VERSION 5.8 ;
BUSBITCHARS "[]" ;
DIVIDERCHAR "/" ;
UNITS
    DATABASE MICRONS 1000 ;
END UNITS

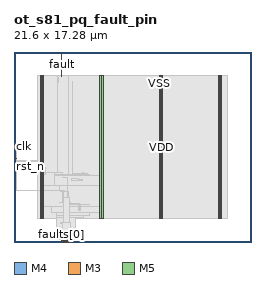
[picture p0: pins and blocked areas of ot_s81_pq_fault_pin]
MACRO ot_s81_pq_fault_pin
  FOREIGN ot_s81_pq_fault_pin 0 0 ;
  CLASS BLOCK ;
  SIZE 21.6 BY 17.28 ;
  PIN clk
    DIRECTION INPUT ;
    USE SIGNAL ;
    PORT
      LAYER M4 ;
        RECT  0 8.64 0.192 8.664 ;
    END
    PORT
      LAYER M4 ;
        RECT  0.156 8.64 0.275 8.664 ;
    END
  END clk
  PIN fault
    DIRECTION OUTPUT ;
    USE SIGNAL ;
    PORT
      LAYER M3 ;
        RECT  4.32 17.136 4.338 17.28 ;
    END
    PORT
      LAYER M3 ;
        RECT  4.32 15.061 4.338 17.148 ;
    END
  END fault
  PIN faults[0]
    DIRECTION INPUT ;
    USE SIGNAL ;
    PORT
      LAYER M3 ;
        RECT  4.32 0 4.338 0.144 ;
    END
  END faults[0]
  PIN faults[10]
    DIRECTION INPUT ;
    USE SIGNAL ;
    PORT
      LAYER M3 ;
        RECT  4.86 0 4.878 0.144 ;
    END
  END faults[10]
  PIN faults[11]
    DIRECTION INPUT ;
    USE SIGNAL ;
    PORT
      LAYER M5 ;
        RECT  4.8 0 4.824 0.192 ;
    END
  END faults[11]
  PIN faults[12]
    DIRECTION INPUT ;
    USE SIGNAL ;
    PORT
      LAYER M3 ;
        RECT  4.968 0 4.986 0.144 ;
    END
  END faults[12]
  PIN faults[13]
    DIRECTION INPUT ;
    USE SIGNAL ;
    PORT
      LAYER M5 ;
        RECT  4.896 0 4.92 0.192 ;
    END
  END faults[13]
  PIN faults[14]
    DIRECTION INPUT ;
    USE SIGNAL ;
    PORT
      LAYER M3 ;
        RECT  5.076 0 5.094 0.144 ;
    END
  END faults[14]
  PIN faults[15]
    DIRECTION INPUT ;
    USE SIGNAL ;
    PORT
      LAYER M5 ;
        RECT  4.992 0 5.016 0.192 ;
    END
  END faults[15]
  PIN faults[16]
    DIRECTION INPUT ;
    USE SIGNAL ;
    PORT
      LAYER M3 ;
        RECT  5.184 0 5.202 0.144 ;
    END
  END faults[16]
  PIN faults[17]
    DIRECTION INPUT ;
    USE SIGNAL ;
    PORT
      LAYER M5 ;
        RECT  5.088 0 5.112 0.192 ;
    END
  END faults[17]
  PIN faults[1]
    DIRECTION INPUT ;
    USE SIGNAL ;
    PORT
      LAYER M5 ;
        RECT  4.32 0 4.344 0.192 ;
    END
  END faults[1]
  PIN faults[2]
    DIRECTION INPUT ;
    USE SIGNAL ;
    PORT
      LAYER M3 ;
        RECT  4.428 0 4.446 0.144 ;
    END
  END faults[2]
  PIN faults[3]
    DIRECTION INPUT ;
    USE SIGNAL ;
    PORT
      LAYER M5 ;
        RECT  4.416 0 4.44 0.192 ;
    END
  END faults[3]
  PIN faults[4]
    DIRECTION INPUT ;
    USE SIGNAL ;
    PORT
      LAYER M3 ;
        RECT  4.536 0 4.554 0.144 ;
    END
  END faults[4]
  PIN faults[5]
    DIRECTION INPUT ;
    USE SIGNAL ;
    PORT
      LAYER M5 ;
        RECT  4.512 0 4.536 0.192 ;
    END
  END faults[5]
  PIN faults[6]
    DIRECTION INPUT ;
    USE SIGNAL ;
    PORT
      LAYER M3 ;
        RECT  4.644 0 4.662 0.144 ;
    END
  END faults[6]
  PIN faults[7]
    DIRECTION INPUT ;
    USE SIGNAL ;
    PORT
      LAYER M5 ;
        RECT  4.608 0 4.632 0.192 ;
    END
  END faults[7]
  PIN faults[8]
    DIRECTION INPUT ;
    USE SIGNAL ;
    PORT
      LAYER M3 ;
        RECT  4.752 0 4.77 0.144 ;
    END
  END faults[8]
  PIN faults[9]
    DIRECTION INPUT ;
    USE SIGNAL ;
    PORT
      LAYER M5 ;
        RECT  4.704 0 4.728 0.192 ;
    END
  END faults[9]
  PIN rst_n
    DIRECTION INPUT ;
    USE SIGNAL ;
    PORT
      LAYER M4 ;
        RECT  0 7.584 0.192 7.608 ;
    END
    PORT
      LAYER M4 ;
        RECT  0.156 7.584 0.245 7.608 ;
    END
  END rst_n
  PIN VDD
    DIRECTION INOUT ;
    USE POWER ;
    PORT
      LAYER M5 ;
        RECT  18.792 2.151 18.912 15.129 ;
        RECT  13.392 2.151 13.512 15.129 ;
        RECT  7.992 2.151 8.112 15.129 ;
        RECT  2.592 2.151 2.712 15.129 ;
    END
  END VDD
  PIN VSS
    DIRECTION INOUT ;
    USE GROUND ;
    PORT
      LAYER M5 ;
        RECT  18.6 2.137 18.72 15.143 ;
        RECT  13.2 2.137 13.32 15.143 ;
        RECT  7.8 2.137 7.92 15.143 ;
        RECT  2.4 2.137 2.52 15.143 ;
    END
  END VSS
  # OT_OBS_CLOSED layer=M5 d_um=1.536 added=0
  OBS
    LAYER RVTN ;
     RECT  2.16 2.16 19.44 2.295 ;
     RECT  2.16 2.565 19.44 2.835 ;
     RECT  2.16 3.105 19.44 3.375 ;
     RECT  2.16 3.645 19.44 3.915 ;
     RECT  2.16 4.185 19.44 4.455 ;
     RECT  2.16 4.725 19.44 4.995 ;
     RECT  2.16 5.265 19.44 5.535 ;
     RECT  2.16 5.805 19.44 6.075 ;
     RECT  2.16 6.345 19.44 6.615 ;
     RECT  2.16 6.885 19.44 7.155 ;
     RECT  2.16 7.425 19.44 7.695 ;
     RECT  2.16 7.965 19.44 8.235 ;
     RECT  2.16 8.505 19.44 8.775 ;
     RECT  2.16 9.045 19.44 9.315 ;
     RECT  2.16 9.585 19.44 9.855 ;
     RECT  2.16 10.125 19.44 10.395 ;
     RECT  2.16 10.665 19.44 10.935 ;
     RECT  2.16 11.205 19.44 11.475 ;
     RECT  2.16 11.745 19.44 12.015 ;
     RECT  2.16 12.285 19.44 12.555 ;
     RECT  2.16 12.825 19.44 13.095 ;
     RECT  2.16 13.365 19.44 13.635 ;
     RECT  2.16 13.905 19.44 14.175 ;
     RECT  2.16 14.445 19.44 14.715 ;
     RECT  2.16 14.985 19.44 15.12 ;
    LAYER RVTP ;
     RECT  2.16 2.295 19.44 2.565 ;
     RECT  2.16 2.835 19.44 3.105 ;
     RECT  2.16 3.375 19.44 3.645 ;
     RECT  2.16 3.915 19.44 4.185 ;
     RECT  2.16 4.455 19.44 4.725 ;
     RECT  2.16 4.995 19.44 5.265 ;
     RECT  2.16 5.535 19.44 5.805 ;
     RECT  2.16 6.075 19.44 6.345 ;
     RECT  2.16 6.615 19.44 6.885 ;
     RECT  2.16 7.155 19.44 7.425 ;
     RECT  2.16 7.695 19.44 7.965 ;
     RECT  2.16 8.235 19.44 8.505 ;
     RECT  2.16 8.775 19.44 9.045 ;
     RECT  2.16 9.315 19.44 9.585 ;
     RECT  2.16 9.855 19.44 10.125 ;
     RECT  2.16 10.395 19.44 10.665 ;
     RECT  2.16 10.935 19.44 11.205 ;
     RECT  2.16 11.475 19.44 11.745 ;
     RECT  2.16 12.015 19.44 12.285 ;
     RECT  2.16 12.555 19.44 12.825 ;
     RECT  2.16 13.095 19.44 13.365 ;
     RECT  2.16 13.635 19.44 13.905 ;
     RECT  2.16 14.175 19.44 14.445 ;
     RECT  2.16 14.715 19.44 14.985 ;
    LAYER M1 ;
     RECT  2.16 2.151 19.44 15.129 ;
    LAYER M2 ;
     RECT  0.211 7.362 2.16 7.38 ;
     RECT  2.16 2.151 3.955 15.129 ;
     RECT  3.955 2.106 4.919 15.129 ;
     RECT  4.855 0.144 4.963 0.162 ;
     RECT  4.963 0.144 5.135 0.234 ;
     RECT  5.135 0.216 5.567 0.234 ;
     RECT  4.919 2.151 19.44 15.129 ;
    LAYER M3 ;
     RECT  4.32 0.108 5.202 0.187 ;
     RECT  3.852 0.187 5.346 0.211 ;
     RECT  3.852 0.211 5.562 2.263 ;
     RECT  6.3 2.191 6.318 2.263 ;
     RECT  3.852 2.263 6.318 2.371 ;
     RECT  2.415 2.143 2.505 2.413 ;
     RECT  7.815 2.143 7.905 2.413 ;
     RECT  13.215 2.143 13.305 2.413 ;
     RECT  18.615 2.143 18.705 2.413 ;
     RECT  3.852 2.371 6.822 2.641 ;
     RECT  7.815 2.413 8.097 2.641 ;
     RECT  2.415 2.413 2.697 3.271 ;
     RECT  3.42 2.641 8.097 3.271 ;
     RECT  2.415 3.271 8.097 5.117 ;
     RECT  3.708 5.117 8.097 6.071 ;
     RECT  3.708 6.071 6.858 6.107 ;
     RECT  2.415 5.117 2.697 6.115 ;
     RECT  3.708 6.107 6.678 6.143 ;
     RECT  5.292 6.143 6.678 6.269 ;
     RECT  2.415 6.115 2.862 6.277 ;
     RECT  3.708 6.143 4.374 6.277 ;
     RECT  6.228 6.269 6.282 6.305 ;
     RECT  2.415 6.277 4.374 6.317 ;
     RECT  4.068 6.317 4.086 6.341 ;
     RECT  6.264 6.305 6.282 6.341 ;
     RECT  2.415 6.317 2.862 6.809 ;
     RECT  2.415 6.809 2.697 6.925 ;
     RECT  2.376 6.925 2.697 7.349 ;
     RECT  0.216 7.357 0.234 7.613 ;
     RECT  3.924 14.521 4.086 14.639 ;
     RECT  5.292 6.269 5.31 14.639 ;
     RECT  2.415 7.349 2.697 14.867 ;
     RECT  7.815 6.071 8.097 14.867 ;
     RECT  13.215 2.413 13.497 14.867 ;
     RECT  18.615 2.413 18.897 14.867 ;
     RECT  4.068 14.639 4.086 14.945 ;
     RECT  2.415 14.867 2.505 15.137 ;
     RECT  7.815 14.867 7.905 15.137 ;
     RECT  13.215 14.867 13.305 15.137 ;
     RECT  18.615 14.867 18.705 15.137 ;
    LAYER M4 ;
     RECT  0.229 4.704 2.408 4.728 ;
     RECT  2.408 2.148 2.512 15.132 ;
     RECT  2.512 2.418 2.704 14.862 ;
     RECT  2.704 4.704 4.097 5.112 ;
     RECT  4.097 4.704 4.273 4.728 ;
     RECT  4.129 3.552 4.381 3.576 ;
     RECT  4.273 4.56 4.381 4.728 ;
     RECT  2.704 6.288 4.385 6.312 ;
     RECT  4.381 3.552 4.525 4.728 ;
     RECT  3.841 0.192 4.556 0.216 ;
     RECT  4.525 3.456 4.565 4.728 ;
     RECT  4.273 1.728 4.652 1.752 ;
     RECT  4.565 3.456 4.669 4.632 ;
     RECT  4.652 1.728 4.739 2.28 ;
     RECT  4.669 3.36 4.796 4.632 ;
     RECT  4.796 2.784 4.883 4.632 ;
     RECT  4.453 5.856 4.883 5.88 ;
     RECT  4.556 0.192 4.885 0.552 ;
     RECT  4.883 3.456 4.924 4.632 ;
     RECT  4.885 0.192 4.969 0.6 ;
     RECT  4.924 3.456 5.027 4.008 ;
     RECT  4.739 1.728 5.123 1.752 ;
     RECT  5.027 3.456 5.177 3.624 ;
     RECT  4.969 0.192 5.357 0.216 ;
     RECT  5.177 3.456 5.893 3.48 ;
     RECT  5.209 5.616 5.897 5.784 ;
     RECT  5.893 2.88 5.933 3.48 ;
     RECT  5.933 2.88 6.005 3.432 ;
     RECT  5.897 5.616 6.221 5.64 ;
     RECT  6.005 3.408 6.833 3.432 ;
     RECT  7.808 2.148 7.912 15.132 ;
     RECT  7.912 2.418 8.104 14.862 ;
     RECT  13.208 2.148 13.312 15.132 ;
     RECT  13.312 2.418 13.504 14.862 ;
     RECT  18.608 2.148 18.712 15.132 ;
     RECT  18.712 2.418 18.904 14.862 ;
    LAYER M5 ;
     RECT  4.32 0.144 5.112 0.227 ;
     RECT  4.416 0.227 5.112 1.763 ;
     RECT  2.4 2.137 2.52 2.151 ;
     RECT  7.8 2.137 7.92 2.151 ;
     RECT  13.2 2.137 13.32 2.151 ;
     RECT  18.6 2.137 18.72 2.151 ;
     RECT  4.512 1.763 5.016 4.019 ;
     RECT  4.512 4.019 4.872 4.595 ;
     RECT  4.848 4.595 4.872 5.891 ;
     RECT  0.24 4.693 0.264 8.675 ;
     RECT  2.4 2.151 2.712 15.129 ;
     RECT  7.8 2.151 8.112 15.129 ;
     RECT  13.2 2.151 13.512 15.129 ;
     RECT  18.6 2.151 18.912 15.129 ;
     RECT  2.4 15.129 2.52 15.143 ;
     RECT  7.8 15.129 7.92 15.143 ;
     RECT  13.2 15.129 13.32 15.143 ;
     RECT  18.6 15.129 18.72 15.143 ;
  END
END ot_s81_pq_fault_pin
END LIBRARY
